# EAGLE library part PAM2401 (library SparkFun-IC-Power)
PAM2401 - Boost PMIC Specifications: Up to 1A output current 0.9V to 4.75V Input Range 2.5V to 5.0V Adjustable Output Voltage Datasheet (Diodes inc.)

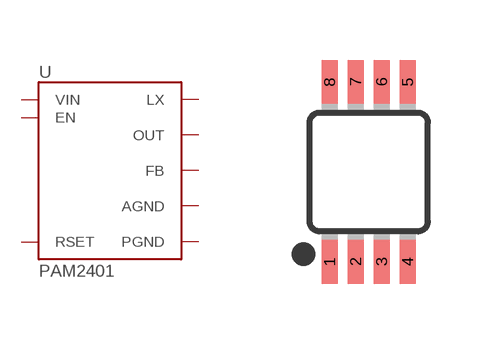
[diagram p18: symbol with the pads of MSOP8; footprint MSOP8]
Designator prefix U

## PAM2401 (PROD_ID: IC-13769; VALUE: PAM2401)  [MSOP8]
1  LX
2  EN
3  VIN
4  AGND
5  FB
6  RSET
7  OUT
8  PGND

## Footprint MSOP8 (pad centres in mm)
8M, 8-Lead, 0.118" Wide, Miniature Small Outline Package MSOP 8M-Package doc1097.pdf
smd 0.4 x 1.1: 1 -0.975,-2.25; 2 -0.325,-2.25; 3 0.325,-2.25; 4 0.975,-2.25; 5 0.975,2.25; 6 0.325,2.25; 7 -0.325,2.25; 8 -0.975,2.25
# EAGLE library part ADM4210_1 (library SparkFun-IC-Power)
Hot Swap Controller (In-Rush Current Limiter)

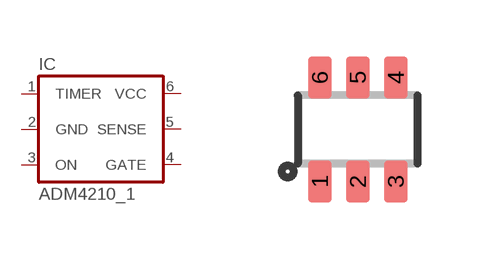
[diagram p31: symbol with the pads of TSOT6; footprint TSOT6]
Designator prefix IC

## ADM4210_1TSOT6 (PROD_ID: IC-14694)  [TSOT6]
1  TIMER  in
2  GND  pwr
3  ON  in
4  GATE  out
5  SENSE  in
6  VCC  pwr

## Footprint TSOT6 (pad centres in mm)
smd 0.6 x 1.05: 1 -0.95,-1.3; 2 0,-1.3; 3 0.95,-1.3; 4 0.95,1.3; 5 0,1.3; 6 -0.95,1.3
